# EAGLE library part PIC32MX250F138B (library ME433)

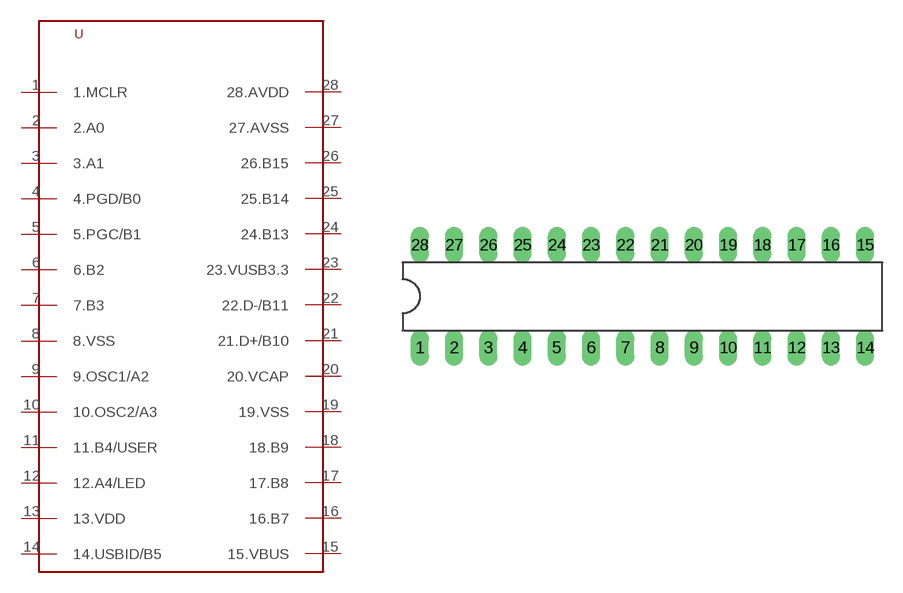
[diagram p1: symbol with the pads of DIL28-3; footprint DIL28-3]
Designator prefix -

## PIC32MX250F138B  [DIL28-3]
1  1.MCLR
2  2.A0
3  3.A1
4  4.PGD/B0
5  5.PGC/B1
6  6.B2
7  7.B3
8  8.VSS
9  9.OSC1/A2
10  10.OSC2/A3
11  11.B4/USER
12  12.A4/LED
13  13.VDD
14  14.USBID/B5
15  15.VBUS
16  16.B7
17  17.B8
18  18.B9
19  19.VSS
20  20.VCAP
21  21.D+/B10
22  22.D-/B11
23  23.VUSB3.3
24  24.B13
25  25.B14
26  26.B15
27  27.AVSS
28  28.AVDD

## Footprint DIL28-3 (pad centres in mm)
Dual In Line package type P
drill 0.813 long: 1 -16.51,-3.81; 2 -13.97,-3.81; 3 -11.43,-3.81; 4 -8.89,-3.81; 5 -6.35,-3.81; 6 -3.81,-3.81; 7 -1.27,-3.81; 8 1.27,-3.81; 9 3.81,-3.81; 10 6.35,-3.81; 11 8.89,-3.81; 12 11.43,-3.81; 13 13.97,-3.81; 14 16.51,-3.81; 15 16.51,3.81; 16 13.97,3.81; 17 11.43,3.81; 18 8.89,3.81; 19 6.35,3.81; 20 3.81,3.81; 21 1.27,3.81; 22 -1.27,3.81; 23 -3.81,3.81; 24 -6.35,3.81; 25 -8.89,3.81; 26 -11.43,3.81; 27 -13.97,3.81; 28 -16.51,3.81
